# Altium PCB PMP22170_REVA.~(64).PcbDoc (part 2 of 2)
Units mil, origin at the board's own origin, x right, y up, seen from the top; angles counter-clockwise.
Board outline 3070.87 x 1889.76 mil, 2 copper layers (Top Layer, Bottom Layer), stack 64.8 mil thick; 75 components, 28 nets, 162 pads, 116 vias.

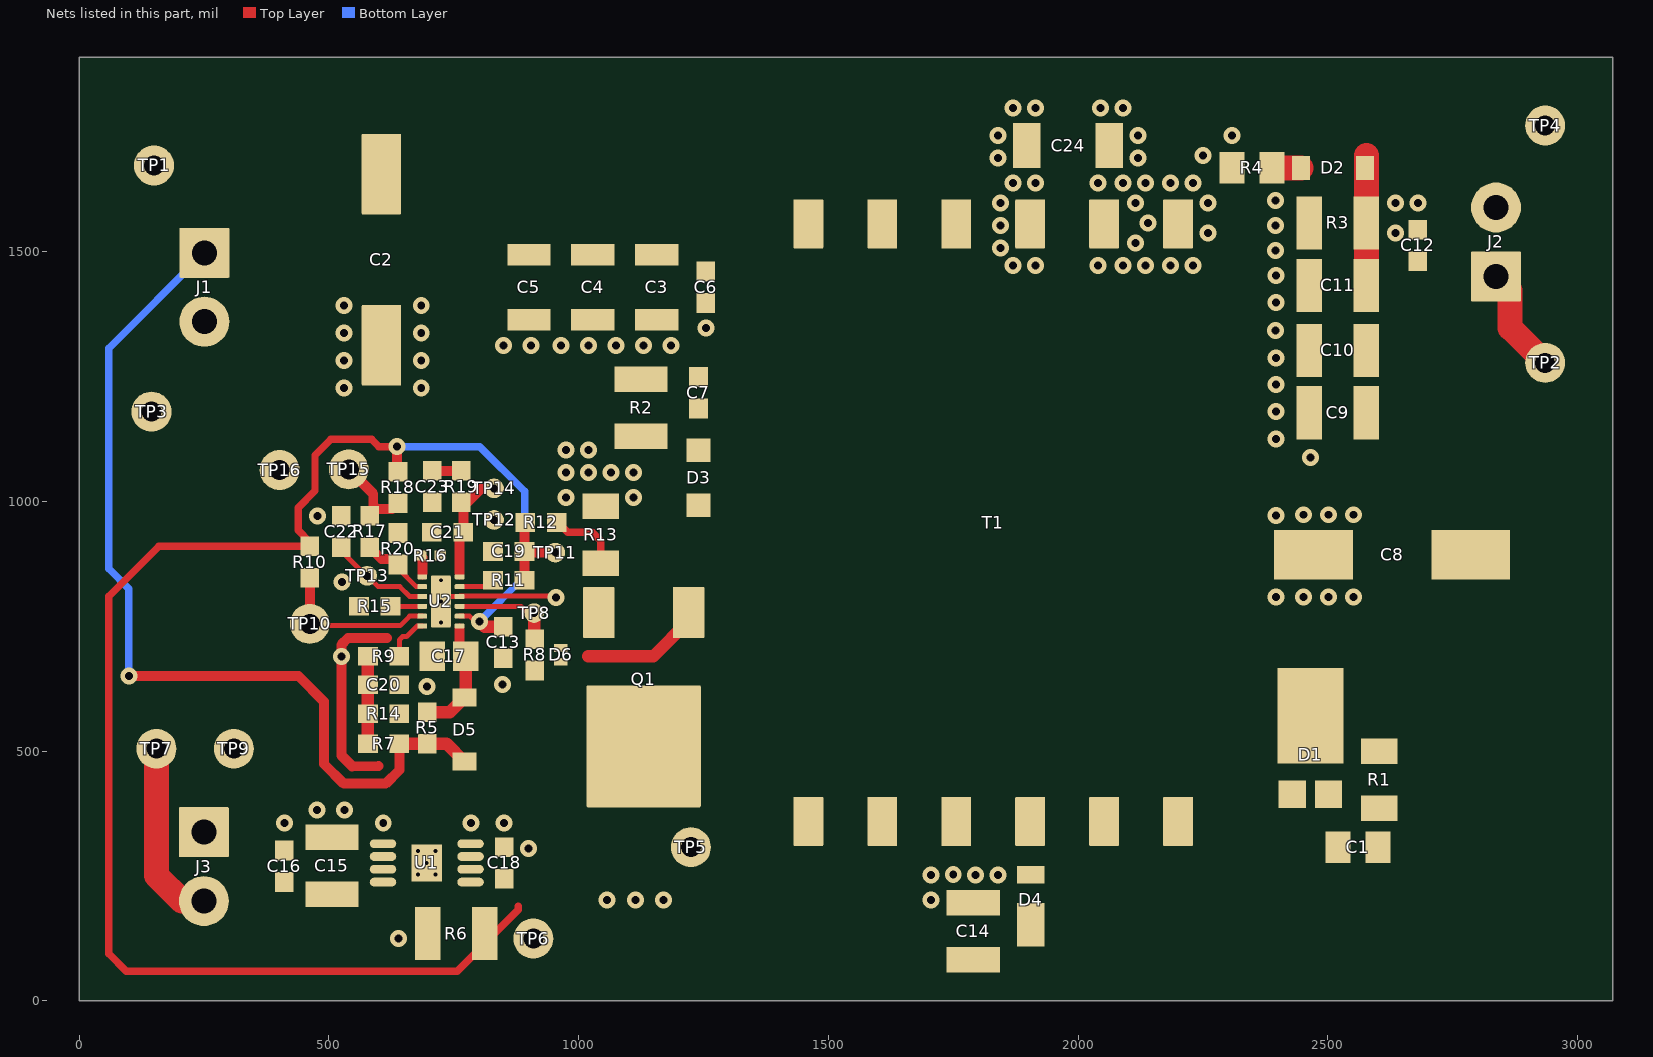
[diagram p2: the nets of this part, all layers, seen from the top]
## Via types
v1: diameter 34, hole 16, Top Layer to Bottom Layer, 108 vias
v2: diameter 19.68, hole 7.87, Top Layer to Bottom Layer, 8 vias

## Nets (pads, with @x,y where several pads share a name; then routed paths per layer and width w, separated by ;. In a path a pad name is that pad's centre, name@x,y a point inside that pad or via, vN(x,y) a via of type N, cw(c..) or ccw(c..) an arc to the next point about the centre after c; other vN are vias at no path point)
GND: C2.1 C3.2 C4.2 C5.2 C6.2 C13.2 C14.2 C15.2 C16.2 C17.2 C18.2 C19.2 C20.2 C21.2 C22.2 C23.2 C24.2 J1.2 J3.1 R6.1 R13.1 R14.1 R15.1 R16.1 R20.1 T1.9 TP3.1 TP9.1 TP12.1 TP16.1 U1.3 U1.4 U1.5 U1.6 U1.7 U1.9 U2.4 U2.13@724.57,799.93 | length 637.9
  Top Layer w10: v2(724.57,799.93) 734.41,809.77 U2.4@761.97,809.77 762.88,810.67 951.87,810.67 v1(954.59,807.96)
  Top Layer w20: 599.64,470 546.97,469.93 525.05,491.85 v1(525.05,689.93) 525.05,712.98 538.57,726.5 616.97,726.5
  other v1: 640,125 1057.21,202.59 1114.17,202.59 1170,202.59 1705.14,202.59 1705.14,252.59 1750.14,252.79 1795.14,252.59 1840.14,252.59 900,305 411.18,356.05 609.07,356.05 784.25,356.05 851.18,356.05 476.18,382.62 531.18,382.62 696.97,629.93 847.52,633.86 526.97,838.43 830.89,962.96 476.97,971.3 975.14,1007.59 1110.14,1007.59 975.14,1057.59 1020.14,1057.59 1065.14,1057.59 1110.14,1057.59 975.14,1102.59 1020.14,1102.59 530.14,1227.59 685.14,1227.59 530.14,1282.59 685.14,1282.59 849.9,1312.46 904.9,1312.46 964.9,1312.46 1019.9,1312.46 1075.14,1312.46 1130.14,1312.46 1184.9,1312.46 530.14,1337.59 685.14,1337.59 1255.14,1347.59 530.14,1392.59 685.14,1392.59 1870.14,1472.59 1915.14,1472.59 1845.14,1507.59 1845.14,1552.59 1845.14,1597.59 1870.14,1637.59 1915.14,1637.59 1840.14,1687.59 1840.14,1732.59 1870.14,1787.59 1915.14,1787.59
  other v2: 678.47,252.86 713.9,252.86 696.18,276.48 678.47,300.1 713.9,300.1 724.57,757.6 724.57,842.25
GND2: C8.2 C9.2 C10.2 C11.2 C12.2 C24.1 J2.2 R3.1 R4.1 T1.7 T1.8 TP4.1
  other v1: 2396.36,808.4 2451.36,808.4 2501.36,808.4 2551.36,808.4 2396.36,972.18 2451.36,973.4 2501.36,973.4 2551.36,973.4 2465.14,1087.59 2396.36,1124.91 2396.36,1179.91 2396.36,1233.73 2396.36,1287.59 2395.14,1342.59 2396.36,1397.83 2396.36,1452.28 2040.14,1472.59 2090.14,1472.59 2135.14,1472.59 2185.14,1472.59 2230.14,1472.59 2395.14,1502.59 2115.14,1517.59 2260.14,1537.59 2635.14,1537.59 2395.14,1552.59 2140.14,1557.59 2115.14,1597.55 2260.14,1597.59 2635.14,1597.55 2680.14,1597.59 2395.14,1602.59 2040.14,1637.59 2090.14,1637.59 2135.14,1637.59 2185.14,1637.59 2230.14,1637.59 2120.14,1687.59 2250.14,1692.59 2120.14,1732.59 2307.91,1732.59 2045.14,1787.59 2090.14,1787.59
NetC1_1: C1.1 R1.1
NetC1_2: C1.2 D1.1 D1.2 T1.5 T1.6
NetC2_2: C2.2 C3.1 C4.1 C5.1 C6.1 C7.1 D5.2 J1.1 R2.2 R5.2 R7.2 T1.10 T1.11 T1.12 TP1.1 | length 1857.7
  Top Layer w20: v1(99.81,650.52) 439.21,650.52 490.52,599.21 490.52,474.48 530.06,434.94 614.06,434.94 641.42,462.3 R7.2@641.42,514.89
  Top Layer w25: R7.2@641.42,514.89 641.78,515.24 R5.2@696.97,515.24 ; R5.2@696.18,514.45 R5.2@696.97,515.24 ; D5.2@771.97,478.96 735.69,515.24 R5.2@696.97,515.24
  Bottom Layer w15: v1(99.81,650.52) 99.81,825.19 60,865 60,1306.79 J1.1@251.05,1497.83
NetC7_2: C7.2 D3.1 R2.1
NetC8_1: C8.1 C9.1 C10.1 C11.1 C12.1 D1.3 D2.1 J2.1 R1.2 R3.2 TP2.1 | length 473.7
  Top Layer w50: C11.1@2577.23,1432.59 2577.23,1692.59 ; J2.1@2836.64,1450.48 2865.14,1421.98 2865.14,1347.59 TP2.1@2935.14,1277.59
NetC13_1: C13.1 C14.1 C18.1 D4.1 R6.2 R10.1 R18.2 TP6.1 U1.1 U1.2 U2.2 | length 3178
  Top Layer w10: U2.2@761.97,770.4 782.03,770.4 792.5,759.93 v1(801.97,759.93)
  Top Layer w15: v1(636.97,1109.93) 600.55,1109.93 585.56,1124.91 504.42,1124.91 472.44,1092.94 472.44,1021.54 438.77,987.87 438.77,941.98 461.97,918.78 R10.1@461.97,910.28 461.58,909.89 160,909.89 60,809.89 60,95 95,60 757.03,60 879.32,182.28 879.32,190
  Top Layer w20: v1(636.97,1109.93) 636.97,1060.97 R18.2@638.47,1059.47
  Top Layer w25: v1(801.97,759.93) 812.45,749.45 C13.1@849.59,749.45
  Bottom Layer w15: v1(636.97,1109.93) 802.62,1109.93 891.86,1020.69 891.86,849.81 v1(801.97,759.93)
NetC15_1: C15.1 C16.1 J3.2 TP7.1 U1.8 | length 370.2
  Top Layer w50: TP7.1@155,505 155,250.92 205.93,200 J3.2@250,200
NetC17_1: C17.1 D5.1 R5.1 U2.1 | length 235.8
  Top Layer w10: 761.97,744.93 U2.1@761.97,750.71
  Top Layer w20: 761.97,744.93 761.97,701.82 C17.1@773.9,689.89
  Top Layer w25: R5.1@696.97,578.23 742.31,578.23 D5.1@771.97,607.9 773.9,609.83 C17.1@773.9,689.89
NetC19_1: C19.1 R11.2 R12.1 TP11.1 | length 178.8
  Top Layer w20: R11.2@891.86,842.25 C19.1@891.86,899.93 ; R12.1@893.09,957.96 891.86,956.72 C19.1@891.86,899.93 ; v1(953.43,897.49) 894.3,897.49 C19.1@891.86,899.93
NetC20_1: C20.1 R7.1 R9.1 R14.2 | length 175
  Top Layer w25: R7.1@578.43,514.89 C20.1@578.43,632.93 R9.1@578.43,689.93
NetC21_1: C21.1 R19.2 TP14.1 U2.6 | length 231
  Top Layer w10: U2.6@761.97,849.14 761.97,857.01
  Top Layer w20: 761.97,857.01 761.97,930.93 C21.1@769.47,938.43 769.47,994.43 R19.2@765.48,998.43 777.52,998.43 805.38,1026.29 v1(830.89,1026.29)
NetC22_1: C22.1 TP13.1 U2.9 | length 207.4
  Top Layer w10: C22.1@525.05,908.31 525.05,900.71 574.53,851.23 v1(576.97,851.23) 598.75,829.45 642.17,829.45 661.86,809.77 U2.9@687.17,809.77
NetC23_1: C23.1 R19.1 | length 58.5
  Top Layer w20: C23.1@706.97,1061.42 R19.1@765.48,1061.42
NetD2_2: D2.2 R4.2 | length 57.9
  Top Layer w50: R4.2@2387.91,1667.59 D2.2@2445.84,1667.59
NetD3_2: D3.2 Q1.2 T1.1 T1.2 T1.3 TP5.1
NetD4_2: D4.2 T1.4
NetD6_1: D6.1 R8.2 TP8.1 U2.3 | length 212.9
  Top Layer w10: U2.3@761.97,790.08 884.73,790.08 898.31,776.5 v1(911.11,776.5)
  Top Layer w25: v1(911.11,776.5) 911.11,725.61 R8.2@912.27,724.45 R8.2@916.21,720.52
NetD6_2: D6.2 Q1.1 R8.1 | length 246.7
  Top Layer w25: 1019.87,689.89 1149.55,689.89 1220.26,760.6 Q1.1@1220.26,777.56
NetQ1_3: Q1.3 R12.2 R13.2 | length 148.1
  Top Layer w15: R12.2@956.09,957.96 966.09,947.96 968.49,947.96 978.49,937.96 1027.57,937.96 1044.59,920.93 R13.2@1044.59,876.68
NetR9_2: R9.2 U2.12 | length 90.3
  Top Layer w10: R9.2@641.42,689.93 641.42,723.04 647.64,729.26 655.54,729.26 676.99,750.71 U2.12@687.17,750.71
NetR11_1: R11.1 U2.5 | length 72.2
  Top Layer w10: U2.5@761.97,829.45 816.07,829.45 R11.1@828.86,842.25
NetR15_2: R15.2 U2.10 | length 63.7
  Top Layer w10: R15.2@623.47,790.08 U2.10@687.17,790.08
NetR16_2: R16.2 U2.7 | length 43.8
  Top Layer w10: U2.7@687.17,849.14 687.17,857
  Top Layer w20: R16.2@683.84,891.58 687.17,888.25 687.17,857
NetR17_1: R17.1 R18.1 TP15.1 | length 169.3
  Top Layer w20: TP15.1@540.04,1064.38 589.04,1015.38 589.04,991.36 R17.1@595.48,984.93 ; R17.1@581.97,971.42 R17.1@595.48,984.93 ; R18.1@638.47,996.48 626.91,984.93 R17.1@595.48,984.93
NetR17_2: R17.2 R20.2 U2.8 | length 142.5
  Top Layer w10: R20.2@638.47,873.86 638.47,866.02 675.04,829.45 U2.8@687.17,829.45
  Top Layer w20: R17.2@581.97,908.43 605.48,884.93 627.41,884.93 R20.2@638.47,873.86
PG: R10.2 TP10.1 U2.11 | length 326.8
  Top Layer w10: TP10.1@461.97,754.93 465.44,751.46 642.92,751.46 661.86,770.4 U2.11@687.17,770.4
  Top Layer w20: TP10.1@461.97,754.93 R10.2@461.97,847.29
pads on no net: U2.13@724.57,772.96 U2.13@724.57,826.89

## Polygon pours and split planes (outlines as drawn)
NetD6_1 on Top Layer "TOP_LAYER_NETD6_1_P032" (solid, remove dead copper, pour order 32): 978.49,699.26 978.49,713.39 947.79,744.09 893.57,744.09 893.57,704.72 945.27,704.72 950.74,699.26
NetD6_2 on Top Layer "TOP_LAYER_NETD6_2_P008" (solid, remove dead copper, pour order 8): 893.7,681.1 945.38,681.1 950.74,686.46 989.9,686.46 1006.19,702.76 1043.31,702.76 1043.31,677.75 1016.91,677.75 996.23,656.93 944.64,656.93 929.44,641.73 893.7,641.73
GND on Top Layer "TOP_LAYER_GND_P062" (solid, remove dead copper, pour order 62): 0,1885.83 3.94,1889.76 1933.07,1889.76 1933.07,0 0,0
GND2 on Top Layer "TOP_LAYER_GND2_P056" (solid, remove dead copper, pour order 56): 2023.62,1889.76 2023.62,0 3070.87,0 3070.87,1889.76
NetC13_1 on Top Layer "TOP_LAYER_NETC13_1_P054" (solid, remove dead copper, pour order 54): 755.14,172.59 755.14,269.79 832.69,269.79 837.48,265 869.88,265 869.88,246.72 910,206.61 900.16,196.76 894.06,196.76 869.88,172.59
NetC8_1 on Top Layer "TOP_LAYER_NETC8_1_P052" (solid, remove dead copper, pour order 52): 2396.36,472.59 2400.14,476.37 2400.14,742.59 2430.14,772.59 2560.97,772.59 2589.75,801.37 2590.14,983.81 2551.36,1022.59 2551.36,1476.13 2577.82,1502.59 2636.79,1502.59 2885.14,1502.59 2885.14,1374.83 2870.14,1359.83 2752.38,1359.83 2720.14,1327.59 2720.14,1167.59 2865.14,1022.59 2865.14,572.59 2765.14,472.59
NetC1_1 on Top Layer "TOP_LAYER_NETC1_1_P050" (solid, remove dead copper, pour order 50): 2565.14,262.59 2580.14,247.59 2631.64,247.59 2648.92,264.87 2648.92,453.5 2639.8,462.61 2575.16,462.61 2565.14,452.59
NetC1_2 on Top Layer "TOP_LAYER_NETC1_2_P048" (solid, remove dead copper, pour order 48): 2020.14,267.59 2040.14,247.59 2530.14,247.59 2545.14,262.59 2544.86,262.87 2544.86,450.58 2530.14,465.31 2387.42,465.31 2336.98,515.75 2073.28,515.75 2020.14,462.61
NetC8_1 on Top Layer "TOP_LAYER_NETC8_1_P046" (solid, remove dead copper, pour order 46): 2830.14,362.59
NetC13_1 on Top Layer "TOP_LAYER_NETC13_1_P042" (solid, remove dead copper, pour order 42): 1935.14,194.99 1875.14,194.99 1835.77,155.62 961.31,155.62 897.13,219.79 755.14,219.79 755.14,65 762.55,57.59 1943.14,57.59 1943.14,188.63
NetD4_2 on Top Layer "TOP_LAYER_NETD4_2_P040" (solid, remove dead copper, pour order 40): 1865.64,247.09 1865.64,282.09 1845.14,302.59 1845.14,412.59 1855.14,422.59 1920.14,422.59 1935.14,407.59 1935.14,237.59 1930.14,232.59 1880.14,232.59
GND on Top Layer "TOP_LAYER_GND_P038" (solid, remove dead copper, pour order 38): 1695.14,272.59 1660.14,237.59 1006.24,237.59 916.24,327.59 880.14,327.59 880.14,256.61 964.16,172.59 1844.39,172.59 1858.72,186.92 1858.72,259.28 1850.14,267.86 1845.41,272.59
GND on Top Layer "TOP_LAYER_GND_P034" (solid, remove dead copper, pour order 34): 1840.14,282.59
NetD3_2 on Top Layer "TOP_LAYER_NETD3_2_P030" (solid, remove dead copper, pour order 30): 996.24,277.59 946.24,327.59 946.24,553.94 1044.89,652.59 1174.38,652.59 1211.72,689.93 1255.39,689.93 1298.05,732.59 1298.05,874.68 1215.14,957.59 1215.14,1037.59 1670.14,1037.59 1790.14,917.59 1790.14,302.59 1780.14,292.59 1685.14,292.59 1645.34,252.79 1019.87,252.79
NetC7_2 on Top Layer "TOP_LAYER_NETC7_2_P028" (solid, remove dead copper, pour order 28): 1071.99,1189.13 1090.46,1207.59 1271.87,1207.59 1283.53,1195.94 1283.53,1080.98 1270.14,1067.59 1145.14,1067.59 1105.14,1107.59 1071.99,1107.59
NetC2_2 on Top Layer "TOP_LAYER_NETC2_2_P026" (solid, remove dead copper, pour order 26): 645.14,1772.59 1755.14,1772.59 1790.14,1737.59 1790.14,1337.59 1670.14,1217.59 1071.99,1217.59 1070.14,1219.44 1070.14,1272.57 1201.42,1272.57 1241.31,1312.46 1277.92,1312.46 1298.05,1332.59 1298.05,1416.04 1285.14,1428.96 688.03,1428.94 644.37,1472.59
NetC2_2 on Top Layer "TOP_LAYER_NETC2_2_P024" (solid, remove dead copper, pour order 24): 600.67,1773.05 1615.14,1773.05
NetC2_2 on Top Layer "TOP_LAYER_NETC2_2_P020" (solid, remove dead copper, pour order 20): 65.14,1642.59
NetC2_2 on Top Layer "TOP_LAYER_NETC2_2_P018" (solid, remove dead copper, pour order 18): 125.14,1428.94 1273.66,1428.94 1273.68,1428.96 1273.68,1534.05 1245.14,1562.59 895.14,1562.59 684.68,1773.05 130.6,1773.05 95.14,1737.59 95.14,1457.59
NetQ1_3 on Top Layer "TOP_LAYER_NETQ1_3_P016" (solid, remove dead copper, pour order 16): 1088.13,726.5 1094.59,732.96 1094.59,897.96 1089.59,902.96 1000.57,902.96 995.1,897.49 994.59,897.49 994.59,735.3 1003.38,726.5
NetQ1_3 on Top Layer "TOP_LAYER_NETQ1_3_P014" (solid, remove dead copper, pour order 14): 1040.73,777.56
NetC15_1 on Top Layer "TOP_LAYER_NETC15_1_P012" (solid, remove dead copper, pour order 12): 637.14,244.19 637.14,174.59 577.55,115 141.73,115 141.73,245.83 165,269.1 541.28,269.1 559.33,251.05 629.97,251.36
NetC13_1 on Top Layer "TOP_LAYER_NETC13_1_P010" (solid, remove dead copper, pour order 10): 891.18,186.05
GND on Bottom Layer "BOTTOM_LAYER_GND_P060" (solid, remove dead copper, pour order 60): 1933.07,0 1933.07,1889.76 0,1889.76 0,0
GND2 on Bottom Layer "BOTTOM_LAYER_GND2_P058" (solid, remove dead copper, pour order 58): 2023.62,1889.76 2023.62,0 3070.87,0 3070.87,1889.76

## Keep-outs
Keep-Out Layer:
  text ".Layer_Name" at 577,-858.49 h60

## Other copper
Top Layer:
  text ".Layer_Name" at 577,-858.49 h60
Bottom Layer:
  text ".Layer_Name" at 577,-858.49 h60

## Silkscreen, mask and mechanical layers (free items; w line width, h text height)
Top Overlay:
  lines w9: 823.92,645.67 823.98,645.67 834.65,635 834.65,525.08 846.2,511.81
  text "'.PRJ_Number'.PCB_Rev" at 887.53,1787.59 h108.27
  text "VIN" at 23.62,1570.87 h72.83 r270
  text "GND2" at 3055.12,1535.43 h72.83 r90
  text "GND" at 23.62,1421.26 h72.83 r270
  text "VOUT2" at 3055.12,1291.34 h72.83 r90
  text "GND" at 23.62,429.13 h72.83 r270
  text "VOUT1" at 23.62,263.69 h72.83 r270
  text ".Layer_Name" at 577,-858.49 h60
Bottom Overlay:
  text ".Layer_Name" at 577,-858.49 h60
Top Paste:
  text ".Layer_Name" at 577,-858.49 h60
Bottom Paste:
  text ".Layer_Name" at 577,-858.49 h60
Top Solder:
  text ".Layer_Name" at 577,-858.49 h60
  text ".Layer_Name" at 577,-858.49 h60
Bottom Solder:
  text ".Layer_Name" at 577,-858.49 h60
Drill Guide:
  text ".Layer_Name" at 577,-858.49 h60
M1 Board Outline:
  lines w9: 0,0 3070.87,0 3070.87,1889.76 0,1889.76 0,0
  lines w10: 0,0 0,1889.76 3070.87,1889.76 3070.87,0 0,0
  text ".Layer_Name" at 577,-858.49 h60
M2 Board Dimensions:
  rectangle: 0,-275 125,-150
  rectangle: 125,-400 500,-275
  lines w7: 0,-275 1000,-275 ; 125,-400 125,-150 ; 250,-400 250,-150 ; 500,-400 500,-150 ; 750,-400 750,-150 ; 0,-400 1000,-400 1000,-150 0,-150 0,-400
  text ".Layer_Name" at 577,-858.49 h60
M3 3D STEP Top:
  text ".Layer_Name" at 577,-858.49 h60
M4 3D STEP Bottom:
  text ".Layer_Name" at 577,-858.49 h60
M5 Assembly Top:
  lines w5: 1200.14,1132.59 1279.39,1132.59 ; 1200.14,992.59 1200.14,1142.59 1279.39,1142.59 1279.39,992.59 1200.14,992.59
  lines w9: 1205.3,1137.59 1274.39,1137.59
  lines w10: -292,-930.17 6308,-930.17 ; -292,-726.83 6310,-726.83 ; -292,-523.5 -292,-1133.5 3713,-1133.5 6310,-1133.5 6310,-523.5 -291.5,-523.5 -291.5,-1133.5 1284,-1133.5 ; 2173,-1133.5 2173,-523.5 ; 3440,-726.83 3440,-523.5 ; 4280,-726.83 4280,-523.5 ; 4902,-1140 4902,-937.17
  text "COMPONENTS MARKED 'DNP' SHOULD NOT BE POPULATED." at 1153.5,-318.5 h60
  text "ASSEMBLY VARIANT:" at 1153,-434 h60
  text ".VariantName" at 2189,-434 h60
  text "PCB VIEWED FROM TOP SIDE" at -228.5,-655.67 h60
  text "BOARD #:" at 2248,-655.67 h60
  text ".PRJ_Number" at 2793.5,-655.67 h60
  text "REV:" at 3638,-655.67 h60
  text ".PCB_Rev" at 3929.5,-655.67 h60
  text "SVN REV:" at 4476,-655.67 h60
  text ".VersionControl_RevNumber" at 4982,-655.67 h60
  text "TID #:" at 2248,-859 h60
  text ".TID" at 2793.5,-859 h60
  text "PLOT NAME =" at -228.5,-1064.34 h60
  text ".plot_File_Name" at 577,-1064.34 h60
  text "GENERATED    :" at 2250,-1064.34 h60
  text ".Print_Date" at 3119.5,-1064.34 h60
  text ".Print_Time" at 3848.5,-1064.34 h60
  text "TEXAS INSTRUMENTS" at 5113,-1064.34 h60
M6 Assembly Bottom:
  lines w10: -292.5,-727.33 6309.5,-727.33 ; -290.5,-930.67 6309.5,-930.67 ; 1115.5,-1140.5 1115.5,-937.67 ; 1737.5,-727.33 1737.5,-524 ; 2577.5,-727.33 2577.5,-524 ; 3844.5,-1134 3844.5,-524 ; 4733.5,-1134 6309,-1134 6309,-524 -292.5,-524 -292.5,-1134 2304.5,-1134 6309.5,-1134 6309.5,-524
  text "COMPONENTS MARKED 'DNP' SHOULD NOT BE POPULATED." at 6102,-318 h60
  text ".VariantName" at 5058,-434 h60
  text "ASSEMBLY VARIANT:" at 6097,-434 h60
  text ".VersionControl_RevNumber" at 1035.5,-656.17 h60
  text "SVN REV:" at 1541.5,-656.17 h60
  text ".PCB_Rev" at 2088,-656.17 h60
  text "REV:" at 2379.5,-656.17 h60
  text ".PRJ_Number" at 3224,-656.17 h60
  text "BOARD #:" at 3769.5,-656.17 h60
  text "PCB VIEWED FROM BOTTOM SIDE" at 6246,-656.17 h60
  text ".TID" at 3224,-859.5 h60
  text "TID #:" at 3769.5,-859.5 h60
  text "TEXAS INSTRUMENTS" at 904.5,-1064.84 h60
  text ".Print_Time" at 2169,-1064.84 h60
  text ".Print_Date" at 2898,-1064.84 h60
  text "GENERATED    :" at 3767.5,-1064.84 h60
  text ".plot_File_Name" at 5440.5,-1064.84 h60
  text "PLOT NAME =" at 6246,-1064.84 h60
M9 Title Sheet:
  drawing of 57 lines, arcs and shapes, not listed
  text "1" at 739.84,8036.5 h70
  text "2" at 3235.5,8036.5 h70
  text "3" at 5724.84,8036.5 h70
  text "4" at 8231.51,8036.5 h70
  text "5" at 10730.5,8036.5 h70
  text "6" at 13235.5,8036.5 h70
  text "A" at -416.5,6893.5 h70
  text "A" at 14383.5,6893.5 h70
  text "B" at -416.5,4513.5 h70
  text "B" at 14383.5,4513.5 h70
  text "C" at -416.5,2138.5 h70
  text "C" at 14383.5,2138.5 h70
  text "PROJECT TITLE:" at 11343.5,277.5 h45
  text ".PRJ_Title" at 11393.5,144.17 h70
  text "DESIGNED FOR:" at 11343.5,-23.5 h45
  text ".PRJ_Customer" at 11393.5,-163.5 h70
  text "D" at -416.5,-231.5 h70
  text "D" at 14383.5,-231.5 h70
  text "FILE NAME:" at 11343.5,-323.5 h45
  text ".PCB_File_Name_No_Path" at 11393.5,-443.5 h70
  text "Texas Instruments (TI) and/or its licensors do not warrant the accuracy or completeness of this specification" at 6374,-605.34 h45
  text "ENGINEER:" at 11343.5,-613.5 h45
  text "LAYOUT BY:" at 12848.5,-613.5 h45
  text "or any information contained therein. TI and/or its licensors do not warrant that this design will meet" at 6329.01,-718 h45
  text ".PRJ_Engineer" at 11393.5,-768.49 h70
  text ".PCB_Layout" at 12899,-768.49 h70
  text "the specifications, will be suitable for your application or fit for any particular purpose, or will operate in" at 6329.01,-830.67 h45
  text ".Layer_Name" at 577,-858.49 h60
  text "ALTIUM DESIGNER VERSION:" at 12848.5,-923.5 h45
  text "an implementation. TI and/or its licensors do not warrant that the design is production worthy. You should" at 6329.01,-943.33 h45
  text "completely validate and test your design implementation to confirm the system functionality for your application." at 6374,-1056 h45
  text ".print_Scale" at 11393.5,-1056.83 h70
  text ".Application_BuildNumber" at 12899,-1056.83 h70
  text "1" at 739.84,-1263.5 h70
  text "2" at 3235.5,-1263.5 h70
  text "3" at 5724.84,-1263.5 h70
  text "4" at 8231.51,-1263.5 h70
  text "5" at 10730.5,-1263.5 h70
  text "6" at 13235.5,-1263.5 h70
M10 Fab Notes:
  drawing of 189 lines, arcs and shapes, not listed
  text "DESIGN INFORMATION" at 12382.02,6356.17 h60
  text "MIN. TRACK WIDTH:" at 11737.46,6224.05 h60
  text "8" at 12833.7,6224.05 h60
  text "MIL" at 12988.46,6224.05 h60
  text "MIN. CLEARANCE:" at 11737.46,6099.92 h60
  text "0.2" at 12773.7,6099.93 h60
  text "mm" at 12988.46,6099.92 h60
  text "MIN. VIA PAD SIZE:" at 11737.46,5975.8 h60
  text "24" at 12803.71,5975.8 h60
  text "MIL" at 12988.46,5975.8 h60
  text "0.05mm (2MIL)" at 12432.46,5845.9 h60
  text "MINIMUM ANNULAR RING" at 11408.23,5837.67 h60
  text "EXTERNAL" at 13140.46,5837.67 h60
  text "PER" at 11608.23,5727.55 h60
  text "IPC-D-275 CLASS 2 LEVEL C" at 11828.23,5727.54 h60
  text "MIL, HOLES" at 13316.46,5627.07 h60
  text "+/-" at 12924,5618.48 h60
  text "+/-" at 13778,5618.48 h60
  text "REGISTRATION TOLERANCES:" at 11408.23,5617.42 h60
  text "METAL" at 12608,5617.42 h60
  text "5" at 13184.2,5617.42 h60
  text "3" at 14017.2,5617.42 h60
  text "MIL" at 14133.46,5617.42 h60
  text "HOLE SIZE TOLERANCE (UNLESS OTHERWISE SPECIFIED):" at 11408.23,5519.1 h60
  text "+/-" at 13778,5516.23 h60
  text "3" at 14017.2,5515.17 h60
  text "MIL" at 14133.46,5515.17 h60
  text "MATERIAL:" at 11333.46,5377.52 h60
  text "FR-4 High Tg" at 12319.9,5249 h60
  text "X" at 12175.46,5241.01 h60
  text "FR-408" at 11754.46,5236.49 h60
  text "OTHER" at 13242.46,5236.49 h60
  text "62 MIL (1.6mm) +/-10%" at 12074.56,5093.46 h60
  text "X" at 11954.46,5091.01 h60
  text "THICKNESS:" at 11408.23,5085.24 h60
  text "OTHER" at 13359.46,5085.24 h60
  text "TOLERANCE:" at 11408.23,4946.92 h60
  text "X" at 12256.46,4946.92 h60
  text "ANSI IPC-6012 TYPE 3 CLASS 2" at 12434.48,4946.92 h60
  text "OTHER +/-" at 12434.46,4802.73 h60
  text "BOW & TWIST:" at 11408.23,4657.54 h60
  text "X" at 12256.46,4657.54 h60
  text "ANSI IPC-6012 TYPE 3 CLASS 2" at 12434.48,4657.54 h60
  text "OTHER +/-" at 12434.46,4510.85 h60
  text "DRILLING:" at 11333.46,4380.23 h60
  text "NC_DRILL FILES" at 13094.46,4275.04 h60
  text "REFERENCE:" at 11408.23,4271.1 h60
  text "X" at 12065.46,4271.01 h60
  text "AS SHOWN" at 12243.46,4271.1 h60
  text "X" at 12966.46,4271.1 h60
  text "OTHER" at 13392.46,4128.85 h60
  text "PTH COPPER THICKNESS:" at 11407.91,4125.32 h60
  text "X" at 12547.14,4125.32 h60
  text "20-30 um" at 12675.14,4125.32 h60
  text "BOARD FINISH:" at 11333.46,3977.73 h60
  text "SILKSCREEN:" at 11488.68,3867.6 h60
  text "X" at 12446.46,3867.6 h60
  text "TOP" at 12563.46,3867.6 h60
  text "X" at 12956.46,3867.6 h60
  text "BOTTOM" at 13074.46,3867.6 h60
  text "SILKSCREEN COLOR:" at 11488.68,3712.41 h60
  text "X" at 12445.46,3712.41 h60
  text "WHITE" at 12563.46,3712.41 h60
  text "OTHER" at 13074.46,3712.41 h60
  text "X" at 12576.46,3568.96 h60
  text "GREEN" at 12694.46,3568.96 h60
  text "OTHER" at 13312.46,3568.96 h60
  text "SOLDER RESIST COLOR:" at 11488.68,3562.1 h60
  text "X" at 12576.46,3414.71 h60
  text "MATTE" at 12694.46,3414.71 h60
  text "SEMI-GLOSS" at 13312,3414.07 h60
  text "IMMERSION GOLD (ENIG)" at 12394.46,3241.94 h60
  text "ENEPIG" at 13732,3234.72 h60
  text "SURFACE FINISH:" at 11333.46,3233.72 h60
  text "X" at 12216.46,3233.72 h60
  text "IMM. TIN/SILVER OR EQUIV" at 11663,3096.4 h60
  text "OTHER" at 13094.46,3092.47 h60
  text "ARRAY/PANEL:" at 11333.46,2937.09 h60
  text "CUT AND TRIM PER M1 BOARD OUTLINE" at 12394.46,2928.87 h60
  text "N.C. ROUTE" at 12394.46,2792.9 h60
  text "X" at 13082.46,2792.9 h60
  text "V. SCORE" at 13260.46,2792.9 h60
  text "CERTIFICATION:" at 11333.46,2663.77 h60
  text "MATERIALS AND WORKMANSHIP FOR ALL PCBS" at 12058.46,2663.77 h60
  text "TO MEET OR EXCEED THE REQUIREMENTS OF:" at 12058.46,2569.71 h60
  text "X" at 11695.97,2441.08 h60
  text "ANSI IPC-A-600F CLASS ->" at 11823.96,2441.08 h60
  text "X" at 13471.97,2441.08 h60
  text "2" at 13581.96,2441.08 h60
  text "1" at 13266.96,2439.58 h60
  text "3" at 13935.96,2439.58 h60
  text "X" at 12507.97,2293.39 h60
  text "RoHS" at 12635.96,2293.39 h60
  text "OTHER" at 13280.36,2293.39 h60
  text "PER ORDER" at 13677.42,2293.39 h60
  text "ALL BOARDS MUST MEET OR EXCEED UL94-V0 REQUIREMENTS." at 11361,2139.57 h60
  text "PCB MUST BEAR THE UL94V-0 UL REGISTERED MATERIAL ID NUMBER" at 11361,2023.5 h60
  text "ADDITIONAL REQUIREMENTS:" at 11333.46,1854.08 h60
  text "MICROSECTION:" at 11408.23,1746.95 h60
  text "YES" at 12313.96,1746.95 h60
  text "REQUIRED" at 13175.46,1602.62 h60
  text "BARE BOARD ELEC. TEST:" at 11408.23,1599.76 h60
  text "NONE" at 12713.96,1599.76 h60
  text "X" at 13057.46,1599.76 h60
  text "PER ORDER" at 13767.46,1599.76 h60
  text "XX MIL VIAS REQUIRE NON-CONDUCTIVE FILL AND PLANARIZE" at 11576.38,1394.82 h59
  text "XX MIL VIAS REQUIRE CONDUCTIVE FILL AND PLANARIZE" at 11584.38,1290.84 h60
  text "OUTER XX MIL TRACES REQUIRE 50 OHM SINGLE-ENDED IMPEDANCE" at 11583.39,1127.46 h58
  text "LAYER 2 & 3 (INNER LAYERS) XX MIL WIDE, XX MIL SPACE / TRACES REQUIRE 100 OHM DIFFERENTIAL IMPEDANCE" at 11575.39,891.74 h60
  text ".Layer_Name" at 577,-858.49 h60
M11 Gerber Information:
  lines w10: -292,-930.17 6308,-930.17 ; -292,-726.83 6310,-726.83 ; -292,-523.5 -292,-1133.5 3713,-1133.5 6310,-1133.5 6310,-523.5 -291.5,-523.5 -291.5,-1133.5 1284,-1133.5 ; 2173,-1133.5 2173,-523.5 ; 3440,-726.83 3440,-523.5 ; 4280,-726.83 4280,-523.5 ; 4902,-1140 4902,-937.17
  text "ALL ARTWORK VIEWED FROM TOP SIDE" at -228.5,-655.67 h60
  text "BOARD #:" at 2248,-655.67 h60
  text ".PRJ_Number" at 2793.5,-655.67 h60
  text "REV:" at 3638,-655.67 h60
  text ".PCB_Rev" at 3929.5,-655.67 h60
  text "SVN REV:" at 4476,-655.67 h60
  text ".VersionControl_RevNumber" at 4982,-655.67 h60
  text "LAYER NAME =" at -228.5,-858.49 h60
  text "TID #:" at 2248,-859 h60
  text ".TID" at 2793.5,-859 h60
  text "PLOT NAME =" at -228.5,-1064.34 h60
  text ".plot_File_Name" at 577,-1064.34 h60
  text "GENERATED    :" at 2250,-1064.34 h60
  text ".Print_Date" at 3119.5,-1064.34 h60
  text ".Print_Time" at 3848.5,-1064.34 h60
  text "TEXAS INSTRUMENTS" at 5113,-1064.34 h60
M12 Stackup:
  drawing of 191 lines, arcs and shapes, not listed
  text "Layer" at 9724.28,7750.32 h60
  text "Name" at 10134.19,7750.32 h60
  text "Material" at 11063.94,7750.32 h60
  text "Thickness" at 11923.7,7750.32 h60
  text "Constant" at 12573.54,7750.32 h60
  text "Board Layer Stack" at 13143.4,7750.32 h60
  text "1" at 9724.28,7630.32 h60
  text "Top Overlay" at 10134.19,7630.32 h60
  text "2" at 9724.28,7510.32 h60
  text "Top Solder" at 10134.19,7510.32 h60
  text "Solder Resist" at 11063.94,7510.32 h60
  text "0.40mil" at 11923.7,7510.32 h60
  text "3.5" at 12573.54,7510.32 h60
  text "3" at 9724.28,7390.32 h60
  text "Top Layer" at 10134.19,7390.32 h60
  text "Copper" at 11063.94,7390.32 h60
  text "2.80mil" at 11923.7,7390.32 h60
  text "4" at 9724.28,7270.32 h60
  text "Dielectric1" at 10134.19,7270.32 h60
  text "FR-4" at 11063.94,7270.32 h60
  text "59.20mil" at 11923.7,7270.32 h60
  text "4.8" at 12573.54,7270.32 h60
  text "5" at 9724.28,7150.32 h60
  text "Bottom Layer" at 10134.19,7150.32 h60
  text "Copper" at 11063.94,7150.32 h60
  text "2.80mil" at 11923.7,7150.32 h60
  text "6" at 9724.28,7030.32 h60
  text "Bottom Solder" at 10134.19,7030.32 h60
  text "Solder Resist" at 11063.94,7030.32 h60
  text "0.40mil" at 11923.7,7030.32 h60
  text "3.5" at 12573.54,7030.32 h60
  text "7" at 9724.28,6910.32 h60
  text "Bottom Overlay" at 10134.19,6910.32 h60
  text ".Layer_Name" at 577,-858.49 h60
M13 Component Bodies Top:
  text ".Layer_Name" at 577,-858.49 h60
M14 Component Bodies Bottom:
  text ".Layer_Name" at 577,-858.49 h60
M15 Courtyards Top:
  text ".Layer_Name" at 577,-858.49 h60
M16 Courtyards Bottom:
  text ".Layer_Name" at 577,-858.49 h60
Drill Drawing:
  circle w10: c5693.95,3127.1 r27.63
  lines w10: 5666.33,2906.08 5721.58,2906.08 5693.95,2850.83 5666.33,2906.08 ; 5666.33,2975.15 5721.58,2975.15 5721.58,3030.4 5666.33,3030.4 5666.33,2975.15 ; 5666.33,3237.6 5680.14,3237.6 5693.95,3223.79 5707.77,3237.6 5721.58,3237.6 5707.77,3251.42 5721.58,3265.23 5707.77,3265.23 5693.95,3279.04 5680.14,3265.23 5666.33,3265.23 5680.14,3251.42 5666.33,3237.6
  lines w12: 5616.24,2813.53 8847.72,2813.53 ; 5616.24,3310.81 8847.72,3310.81 ; 5954.1,2689.21 5954.1,3435.13 ; 6286.1,2689.21 6286.1,3435.13 ; 6922.66,2689.21 6922.66,3435.13 ; 7181.8,2689.21 7181.8,3435.13 ; 7556.96,2689.21 7556.96,3435.13 ; 8281.29,2689.21 8281.29,3435.13 ; 5616.24,2689.21 8847.72,2689.21 8847.72,3435.13 5616.24,3435.13 5616.24,2689.21
  text "Symbol" at 5690.83,3348.11 h72
  text "Quantity" at 5991.39,3348.11 h72
  text "Finished Hole Size" at 6323.4,3348.11 h72
  text "Plated" at 6959.96,3348.11 h72
  text "Hole Type" at 7219.1,3348.11 h72
  text "Drill Layer Pair" at 7594.26,3348.11 h72
  text "Hole Tolerance" at 8318.59,3348.11 h72
  text "8" at 5991.39,3223.79 h60
  text "7.87mil (0.200mm)" at 6323.4,3223.79 h60
  text "PTH" at 6959.96,3223.79 h60
  text "Round" at 7219.1,3223.79 h60
  text "Top Layer - Bottom Layer" at 7594.26,3223.79 h60
  text "108" at 5991.39,3099.47 h60
  text "16.00mil (0.406mm)" at 6323.4,3099.47 h60
  text "PTH" at 6959.96,3099.47 h60
  text "Round" at 7219.1,3099.47 h60
  text "Top Layer - Bottom Layer" at 7594.26,3099.47 h60
  text "11" at 5991.39,2975.15 h60
  text "40.00mil (1.016mm)" at 6323.4,2975.15 h60
  text "PTH" at 6959.96,2975.15 h60
  text "Round" at 7219.1,2975.15 h60
  text "Top Layer - Bottom Layer" at 7594.26,2975.15 h60
  text "6" at 5991.39,2850.83 h60
  text "50.00mil (1.270mm)" at 6323.4,2850.83 h60
  text "PTH" at 6959.96,2850.83 h60
  text "Round" at 7219.1,2850.83 h60
  text "Top Layer - Bottom Layer" at 7594.26,2850.83 h60
  text "133 Total" at 5991.39,2726.51 h60
  text ".Layer_Name" at 577,-858.49 h60
M17 Embedded Cavity:
  text ".Layer_Name" at 577,-858.49 h60
M18 Embedded Assembly:
  text ".Layer_Name" at 577,-858.49 h60
M19 Embedded Keepout:
  text ".Layer_Name" at 577,-858.49 h60

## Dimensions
0,-400 to 1000,-400 on M2 Board Dimensions
0,0 to 0,1889.76 on M2 Board Dimensions
0,0 to 3070.87,0 on M2 Board Dimensions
